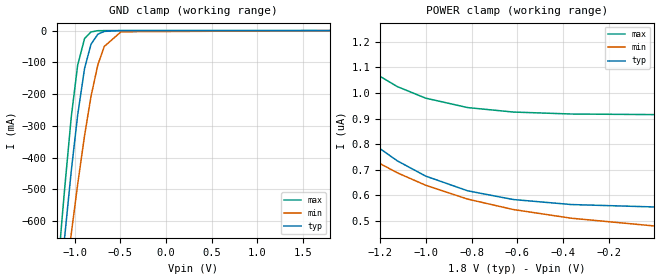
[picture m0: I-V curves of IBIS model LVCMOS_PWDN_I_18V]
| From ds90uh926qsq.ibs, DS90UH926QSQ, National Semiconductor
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[Model] LVCMOS_PWDN_I_18V
Model_type Input
Vinh = 1.17V
Vinl = 0.63V
C_comp   6.98pF   6.05pF   8.06pF
[Voltage Range]   1.8V   1.62V   1.98V
[Temperature Range]   25.0   130.0   -40.0
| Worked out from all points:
|   GND clamp passes 1 mA (typ) near -0.64 V on its own axis
[GND Clamp]
-1.8V     -2.96A     -2.635A    -3.168A
-1.184V   -874.3mA   -993.2mA   -751.4mA
-1.147V   -756.9mA   -899mA     -617.6mA
-1.114V   -658.8mA   -819.6mA   -507.3mA
-1.039V   -442.8mA   -640.4mA   -272.8mA
-968.4mV  -265.6mA   -483.8mA   -108.6mA
-892.8mV  -119mA     -330.2mA   -25.04mA
-822.6mV  -43.25mA   -207.4mA   -4.296mA
-747mV    -11.34mA   -107.3mA   -359.8uA
-676.8mV  -2.575mA   -49.95mA   -22.97uA
-493.2mV  -19.64uA   -3.719mA   -3.559uA
1.796V    555.1nA    0A         915.6nA
[POWER Clamp]
-1.8V     1.463uA    1.175uA    12.75uA
-1.67V    1.264uA    1.05uA     1.588uA
-1.562V   1.121uA    956.7nA    1.407uA
-1.454V   997.1nA    874.8nA    1.273uA
-1.341V   887.9nA    800.2nA    1.162uA
-1.233V   802.8nA    739.5nA    1.082uA
-1.125V   734.9nA    688.3nA    1.025uA
-1.001V   675.6nA    639.8nA    980nA
-817.2mV  618.1nA    585.7nA    943.2nA
-617.4mV  584.1nA    545nA      925.8nA
-363.6mV  564.5nA    511.1nA    918.1nA
-1.8mV    555.1nA    481nA      915.8nA
